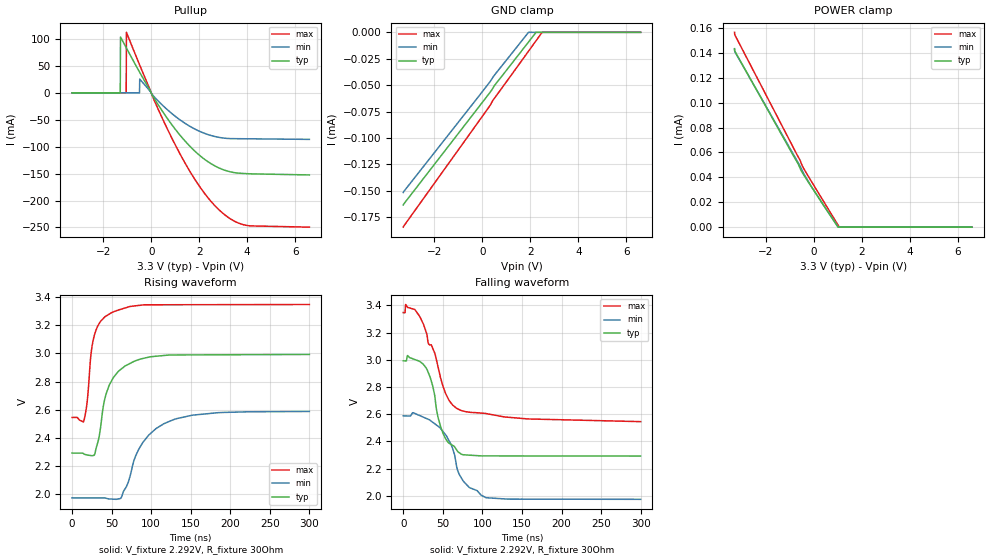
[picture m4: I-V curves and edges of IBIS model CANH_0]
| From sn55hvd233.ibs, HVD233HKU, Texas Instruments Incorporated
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|   Driver (CANH) Output/Receiver Input Model, RS=0
[Model]   CANH_0
Model_type   Open_source
Polarity   Non-Inverting
Vmeas = 1.65
Vref = 2.3
Cref = 15pF
Rref = 50
|   typ   min   max
|   (nom PVT)   (fast PVT)   (slow PVT)
C_comp   37.68p   36.61p   39.23p
|C_comp (Dom state)   44.61p   43.36p   46.74p
|C_comp (Rec state)   37.68p   36.61p   39.23p
[Voltage Range]   3.3   3   3.6
[Temperature Range]   27   150   -40
[Pullup Reference]   3.3   3   3.6
[Pulldown Reference]   -0   -0   -0
[Power Clamp Reference]   3.3   3   3.6
[GND Clamp Reference]   -0   -0   -0
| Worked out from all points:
|   slope of the pullup table from 0 to 0.495 V, typ, clamps not added: 13.8 ohm
|   falling waveform, V_fixture 2.292V, R_fixture 30Ohm: 20-80 % time 17.5ns typ, 26.4ns min, 27.6ns max; typ from 2.99 V to 2.29 V
|   rising waveform, V_fixture 2.292V, R_fixture 30Ohm: 20-80 % time 20.8ns typ, 34.2ns min, 11.9ns max; typ from 2.29 V to 2.99 V
[GND Clamp]
|   Voltage   I(typ)   I(min)   I(max)
-3.3V     -163.5uA   -151.7uA   -184.4uA
254.1mV   -58.68uA   -48.55uA   -71.25uA
462mV     -51.74uA   -41.67uA   -63.54uA
1.917V    -9.218uA   -28.75nA   -17.91uA
2.224V    -259nA     0A         -8.224uA
2.482V    0A         0A         -97.42nA
6.59V     0A         0A         0A
[Pullup]
|   Voltage   I(typ)   I(min)   I(max)
-3.3V     62.9uA     21.06uA    149.5uA
-1.29V    47.71uA    20.71uA    145uA
-1.28V    103.8mA    20.7uA     144.9uA
-1.043V   84.08mA    20.64uA    109.1uA
-1.033V   83.25mA    20.63uA    112.5mA
-488.4mV  38.82mA    17.13uA    52.54mA
-478.5mV  38.03mA    25.63mA    51.48mA
1.175V    -77.18mA   -49.34mA   -111.3mA
1.947V    -113.4mA   -69.96mA   -169.4mA
2.64V     -135.3mA   -80.89mA   -208.9mA
3.887V    -149.8mA   -85.2mA    -245.4mA
6.59V     -152.4mA   -86.35mA   -249.4mA
[POWER Clamp]
|   Voltage   I(typ)   I(min)   I(max)
-3.3V     143.4uA    142.9uA    156.5uA
-3.29V    141.5uA    141.1uA    154.6uA
-656.7mV  51.1uA     52.07uA    56.87uA
-557.7mV  46.79uA    48.59uA    53.25uA
-488.4mV  44.24uA    45.88uA    49.79uA
-132mV    33.52uA    33.68uA    37.88uA
313.5mV   20.5uA     20.37uA    23.79uA
1.006V    216.9nA    408.9nA    1.867uA
1.056V    0A         0A         301.7nA
6.59V     0A         0A         0A
[Ramp]
R_load = 30
|   typ   min   max
dV/dt_r   0.420005/2.03971e-08   0.367998/3.41559e-08   0.480883/1.18883e-08
dV/dt_f   0.420005/1.72789e-08   0.367998/2.57769e-08   0.480883/2.75924e-08
[Falling Waveform]
V_fixture = 2.292V
V_fixture_min = 1.974V
V_fixture_max = 2.545V
R_fixture = 30Ohm
C_fixture = 0F
|   Time   V(typ)   V(min)   V(max)
0s        2.992V     2.587V     3.346V
2.945ns   2.991V     2.587V     3.406V
14.46ns   3.002V     2.606V     3.37V
28.74ns   2.941V     2.569V     3.207V
37.12ns   2.81V      2.541V     3.086V
50.34ns   2.458V     2.471V     2.802V
62.04ns   2.372V     2.354V     2.669V
73.44ns   2.306V     2.131V     2.626V
105.1ns   2.293V     1.986V     2.604V
300ns     2.292V     1.974V     2.545V
[Rising Waveform]
V_fixture = 2.292V
V_fixture_min = 1.974V
V_fixture_max = 2.545V
R_fixture = 30Ohm
C_fixture = 0F
|   Time   V(typ)   V(min)   V(max)
0s        2.292V     1.974V     2.545V
15.72ns   2.284V     1.974V     2.536V
24.04ns   2.274V     1.974V     2.997V
28.12ns   2.277V     1.974V     3.126V
41.47ns   2.678V     1.974V     3.259V
50.03ns   2.805V     1.966V     3.289V
62.04ns   2.888V     1.975V     3.313V
84.52ns   2.956V     2.321V     3.34V
116.1ns   2.985V     2.501V     3.345V
300ns     2.992V     2.587V     3.346V
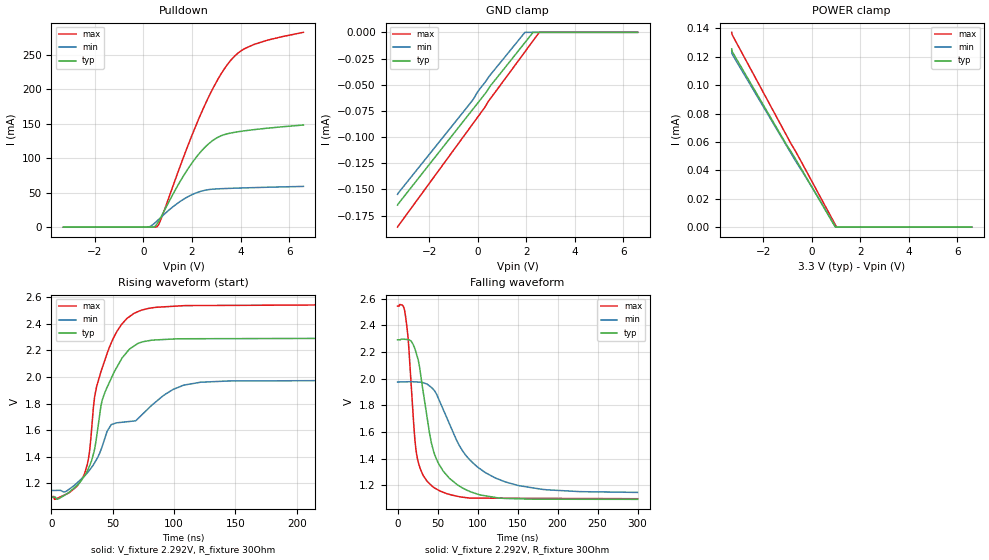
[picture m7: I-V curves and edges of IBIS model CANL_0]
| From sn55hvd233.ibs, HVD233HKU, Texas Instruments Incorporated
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|   Driver (CANL) Output/Receiver Input Model, RS=0
[Model]   CANL_0
Model_type   Open_drain
Polarity   Non-Inverting
Vmeas = 1.65
Vref = 2.3
Cref = 15pF
Rref = 50
|   typ   min   max
|   (nom PVT)   (fast PVT)   (slow PVT)
C_comp   28.10p   26.65p   30.32p
|C_comp (Dom state)   40.48p   34.89p   44.07p
|C_comp (Rec state)   28.10p   26.65p   30.32p
[Voltage Range]   3.3   3   3.6
[Temperature Range]   27   150   -40
[Pullup Reference]   3.3   3   3.6
[Pulldown Reference]   -0   -0   -0
[Power Clamp Reference]   3.3   3   3.6
[GND Clamp Reference]   -0   -0   -0
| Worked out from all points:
|   slope of the pulldown table from 0 to 0.495 V, typ, clamps not added: 269 ohm
|   falling waveform, V_fixture 2.292V, R_fixture 30Ohm: 20-80 % time 25.9ns typ, 51.6ns min, 11.5ns max; typ from 2.29 V to 1.09 V
|   rising waveform, V_fixture 2.292V, R_fixture 30Ohm: 20-80 % time 20.9ns typ, 52.6ns min, 18.5ns max; typ from 1.09 V to 2.29 V
[Pulldown]
|   Voltage   I(typ)   I(min)   I(max)
-3.3V     -104.5nA   -151.2nA   -93.38nA
145.2mV   268.4nA    71.94uA    253.2nA
422.4mV   273.8uA    4.681mA    2.136uA
561mV     4.833mA    9.079mA    726.5uA
788.7mV   19.3mA     16.59mA    17.81mA
1.531V    67.64mA    37.8mA     90.46mA
2.224V    103.8mA    50.46mA    152.9mA
2.838V    125.4mA    55.1mA     199.9mA
3.472V    135.7mA    56.23mA    236.8mA
3.947V    138.8mA    56.8mA     254.2mA
4.531V    141.5mA    57.41mA    265mA
6.59V     148.3mA    59.17mA    282.9mA
[GND Clamp]
|   Voltage   I(typ)   I(min)   I(max)
-3.3V     -164.9uA   -154.7uA   -186uA
-260.7mV  -75.27uA   -66.32uA   -89.26uA
16.5mV    -67.12uA   -56.26uA   -80.46uA
353.1mV   -57.16uA   -46.14uA   -69.44uA
561mV     -50.02uA   -39.45uA   -62.1uA
1.947V    -9.81uA    -35.41nA   -18.63uA
2.274V    -275.6nA   0A         -8.321uA
2.531V    0A         0A         -197nA
6.59V     0A         0A         0A
[POWER Clamp]
|   Voltage   I(typ)   I(min)   I(max)
-3.3V     125.5uA    124uA      137.2uA
-3.29V    123.8uA    122.1uA    135.7uA
-3.251V   122.7uA    120.9uA    134.4uA
-1.053V   58.3uA     57.62uA    64.9uA
-656.7mV  47.53uA    46.29uA    52.96uA
-102.3mV  31.36uA    31.16uA    35.55uA
966.9mV   60.4nA     558.5nA    1.724uA
1.016V    0A         0A         157nA
6.59V     0A         0A         0A
[Ramp]
R_load = 30
|   typ   min   max
dV/dt_r   0.71867/2.06378e-08   0.497274/5.2294e-08   0.867754/1.84855e-08
dV/dt_f   0.71867/2.56336e-08   0.497274/5.12522e-08   0.867754/1.14909e-08
[Falling Waveform]
V_fixture = 2.292V
V_fixture_min = 1.975V
V_fixture_max = 2.545V
R_fixture = 30Ohm
C_fixture = 0F
|   Time   V(typ)   V(min)   V(max)
0s        2.292V     1.975V     2.545V
7.232ns   2.297V     1.976V     2.544V
10.69ns   2.295V     1.977V     2.436V
21.45ns   2.227V     1.976V     1.558V
24.59ns   2.166V     1.975V     1.407V
43.13ns   1.498V     1.93V      1.193V
56.78ns   1.308V     1.773V     1.148V
81.43ns   1.179V     1.457V     1.11V
122ns     1.109V     1.255V     1.103V
300ns     1.094V     1.146V     1.099V
[Rising Waveform]
V_fixture = 2.292V
V_fixture_min = 1.975V
V_fixture_max = 2.545V
R_fixture = 30Ohm
C_fixture = 0F
|   Time   V(typ)   V(min)   V(max)
0s        1.094V     1.146V     1.099V
25.77ns   1.24V      1.245V     1.247V
30.88ns   1.327V     1.297V     1.425V
34.86ns   1.441V     1.349V     1.821V
40.47ns   1.788V     1.454V     2.042V
48.71ns   1.988V     1.64V      2.255V
67.32ns   2.232V     1.669V     2.479V
99.16ns   2.285V     1.906V     2.532V
121.7ns   2.288V     1.961V     2.537V
300ns     2.292V     1.975V     2.545V
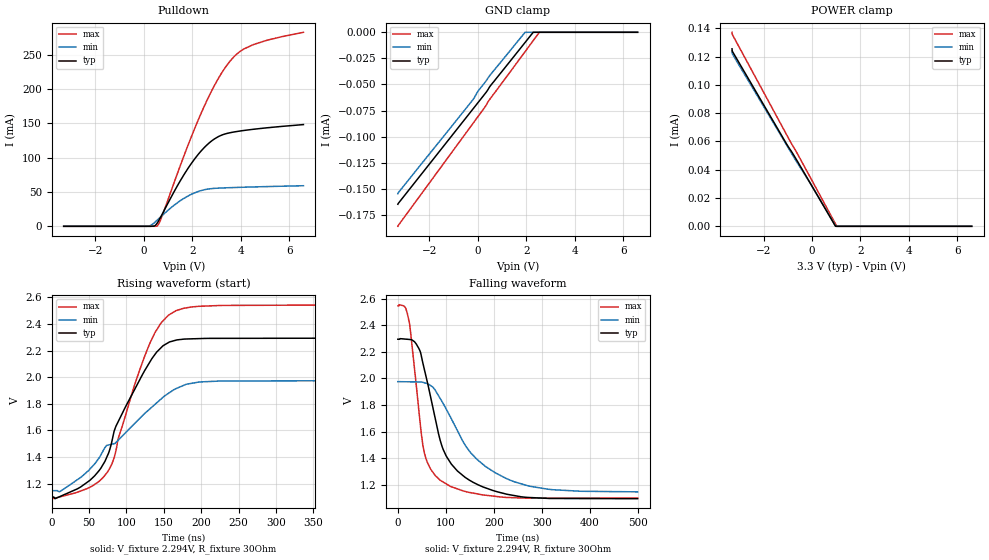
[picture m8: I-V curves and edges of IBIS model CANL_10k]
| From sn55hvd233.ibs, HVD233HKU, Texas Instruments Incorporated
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|   Driver (CANL) Output/Receiver Input Model, RS=10k
[Model]   CANL_10k
Model_type   Open_drain
Polarity   Non-Inverting
Vmeas = 1.65
Vref = 2.3
Cref = 15pF
Rref = 50
|   typ   min   max
|   (nom PVT)   (fast PVT)   (slow PVT)
C_comp   28.10p   26.65p   30.32p
|C_comp (Dom state)   40.48p   34.89p   44.07p
|C_comp (Rec state)   28.10p   26.65p   30.32p
[Voltage Range]   3.3   3   3.6
[Temperature Range]   27   150   -40
[Pullup Reference]   3.3   3   3.6
[Pulldown Reference]   -0   -0   -0
[Power Clamp Reference]   3.3   3   3.6
[GND Clamp Reference]   -0   -0   -0
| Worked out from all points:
|   slope of the pulldown table from 0 to 0.495 V, typ, clamps not added: 269 ohm
|   falling waveform, V_fixture 2.294V, R_fixture 30Ohm: 20-80 % time 60.4ns typ, 98.9ns min, 30.2ns max; typ from 2.29 V to 1.09 V
|   rising waveform, V_fixture 2.294V, R_fixture 30Ohm: 20-80 % time 57.1ns typ, 89.3ns min, 48.3ns max; typ from 1.09 V to 2.29 V
[Pulldown]
|   Voltage   I(typ)   I(min)   I(max)
-3.3V     -104.5nA   -151.2nA   -93.38nA
145.2mV   268.4nA    71.94uA    253.2nA
422.4mV   273.8uA    4.681mA    2.136uA
561mV     4.833mA    9.079mA    726.5uA
788.7mV   19.3mA     16.59mA    17.81mA
1.531V    67.64mA    37.8mA     90.46mA
2.224V    103.8mA    50.46mA    152.9mA
2.838V    125.4mA    55.1mA     199.9mA
3.472V    135.7mA    56.23mA    236.8mA
3.947V    138.8mA    56.8mA     254.2mA
4.531V    141.5mA    57.41mA    265mA
6.59V     148.3mA    59.17mA    282.9mA
[GND Clamp]
|   Voltage   I(typ)   I(min)   I(max)
-3.3V     -164.9uA   -154.7uA   -186uA
-260.7mV  -75.27uA   -66.32uA   -89.26uA
16.5mV    -67.12uA   -56.26uA   -80.46uA
353.1mV   -57.16uA   -46.14uA   -69.44uA
561mV     -50.02uA   -39.45uA   -62.1uA
1.947V    -9.81uA    -35.41nA   -18.63uA
2.274V    -275.6nA   0A         -8.321uA
2.531V    0A         0A         -197nA
6.59V     0A         0A         0A
[POWER Clamp]
|   Voltage   I(typ)   I(min)   I(max)
-3.3V     125.5uA    124uA      137.2uA
-3.29V    123.8uA    122.1uA    135.7uA
-3.251V   122.7uA    120.9uA    134.4uA
-1.053V   58.3uA     57.62uA    64.9uA
-656.7mV  47.53uA    46.29uA    52.96uA
-102.3mV  31.36uA    31.16uA    35.55uA
966.9mV   60.4nA     558.5nA    1.724uA
1.016V    0A         0A         157nA
6.59V     0A         0A         0A
[Ramp]
R_load = 30
|   typ   min   max
dV/dt_r   0.719469/5.6909e-08   0.497274/8.85304e-08   0.867754/4.8261e-08
dV/dt_f   0.719469/5.98566e-08   0.497274/9.83517e-08   0.867754/3.01305e-08
[Falling Waveform]
V_fixture = 2.294V
V_fixture_min = 1.975V
V_fixture_max = 2.545V
R_fixture = 30Ohm
C_fixture = 0F
|   Time   V(typ)   V(min)   V(max)
0s        2.294V     1.975V     2.545V
15.59ns   2.295V     1.974V     2.533V
24.56ns   2.292V     1.974V     2.408V
46.01ns   2.207V     1.973V     1.681V
58.13ns   2.023V     1.964V     1.402V
88.25ns   1.535V     1.849V     1.234V
111.3ns   1.356V     1.698V     1.185V
151.1ns   1.23V      1.444V     1.141V
225.6ns   1.13V      1.248V     1.104V
500ns     1.095V     1.146V     1.099V
[Rising Waveform]
V_fixture = 2.294V
V_fixture_min = 1.975V
V_fixture_max = 2.545V
R_fixture = 30Ohm
C_fixture = 0F
|   Time   V(typ)   V(min)   V(max)
0s        1.095V     1.146V     1.099V
50.85ns   1.224V     1.308V     1.173V
73.91ns   1.402V     1.488V     1.282V
85.83ns   1.63V      1.509V     1.446V
110.2ns   1.9V       1.648V     1.932V
130.9ns   2.111V     1.76V      2.25V
146.4ns   2.222V     1.837V     2.409V
166.4ns   2.278V     1.914V     2.5V
225.6ns   2.292V     1.971V     2.539V
500ns     2.294V     1.975V     2.545V
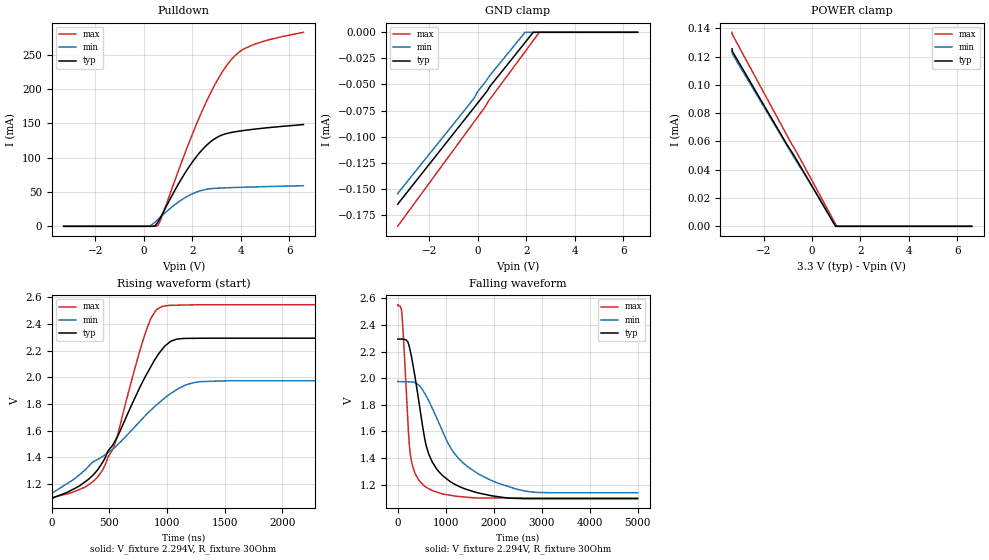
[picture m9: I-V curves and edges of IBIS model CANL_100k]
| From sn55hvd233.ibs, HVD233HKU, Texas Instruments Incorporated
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|   Driver (CANL) Output/Receiver Input Model, RS=100k
[Model]   CANL_100k
Model_type   Open_drain
Polarity   Non-Inverting
Vmeas = 1.65
Vref = 2.3
Cref = 15pF
Rref = 50
|   typ   min   max
|   (nom PVT)   (fast PVT)   (slow PVT)
C_comp   28.10p   26.65p   30.32p
|C_comp (Dom state)   40.48p   34.89p   44.07p
|C_comp (Rec state)   28.10p   26.65p   30.32p
[Voltage Range]   3.3   3   3.6
[Temperature Range]   27   150   -40
[Pullup Reference]   3.3   3   3.6
[Pulldown Reference]   -0   -0   -0
[Power Clamp Reference]   3.3   3   3.6
[GND Clamp Reference]   -0   -0   -0
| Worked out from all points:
|   slope of the pulldown table from 0 to 0.495 V, typ, clamps not added: 269 ohm
|   falling waveform, V_fixture 2.294V, R_fixture 30Ohm: 20-80 % time 443ns typ, 899ns min, 153ns max; typ from 2.29 V to 1.09 V
|   rising waveform, V_fixture 2.294V, R_fixture 30Ohm: 20-80 % time 423ns typ, 638ns min, 301ns max; typ from 1.09 V to 2.29 V
[Pulldown]
|   Voltage   I(typ)   I(min)   I(max)
-3.3V     -104.5nA   -151.2nA   -93.38nA
145.2mV   268.4nA    71.94uA    253.2nA
422.4mV   273.8uA    4.681mA    2.136uA
561mV     4.833mA    9.079mA    726.5uA
788.7mV   19.3mA     16.59mA    17.81mA
1.531V    67.64mA    37.8mA     90.46mA
2.224V    103.8mA    50.46mA    152.9mA
2.838V    125.4mA    55.1mA     199.9mA
3.472V    135.7mA    56.23mA    236.8mA
3.947V    138.8mA    56.8mA     254.2mA
4.531V    141.5mA    57.41mA    265mA
6.59V     148.3mA    59.17mA    282.9mA
[GND Clamp]
|   Voltage   I(typ)   I(min)   I(max)
-3.3V     -164.9uA   -154.7uA   -186uA
-260.7mV  -75.27uA   -66.32uA   -89.26uA
16.5mV    -67.12uA   -56.26uA   -80.46uA
353.1mV   -57.16uA   -46.14uA   -69.44uA
561mV     -50.02uA   -39.45uA   -62.1uA
1.947V    -9.81uA    -35.41nA   -18.63uA
2.274V    -275.6nA   0A         -8.321uA
2.531V    0A         0A         -197nA
6.59V     0A         0A         0A
[POWER Clamp]
|   Voltage   I(typ)   I(min)   I(max)
-3.3V     125.5uA    124uA      137.2uA
-3.29V    123.8uA    122.1uA    135.7uA
-3.251V   122.7uA    120.9uA    134.4uA
-1.053V   58.3uA     57.62uA    64.9uA
-656.7mV  47.53uA    46.29uA    52.96uA
-102.3mV  31.36uA    31.16uA    35.55uA
966.9mV   60.4nA     558.5nA    1.724uA
1.016V    0A         0A         157nA
6.59V     0A         0A         0A
[Ramp]
R_load = 30
|   typ   min   max
dV/dt_r   0.719469/4.20234e-07   0.501556/6.37018e-07   0.867754/3.01847e-07
dV/dt_f   0.719469/4.39533e-07   0.501569/8.9218e-07   0.867754/1.53264e-07
[Falling Waveform]
V_fixture = 2.294V
V_fixture_min = 1.975V
V_fixture_max = 2.545V
R_fixture = 30Ohm
C_fixture = 0F
|   Time   V(typ)   V(min)   V(max)
0s        2.294V     1.975V     2.545V
83.64ns   2.294V     1.974V     2.488V
222.2ns   2.257V     1.972V     1.591V
262.4ns   2.2V       1.972V     1.422V
548.2ns   1.569V     1.894V     1.192V
718.9ns   1.37V      1.773V     1.156V
929.7ns   1.269V     1.604V     1.131V
1.289us   1.185V     1.388V     1.111V
1.916us   1.12V      1.237V     1.101V
5us       1.095V     1.139V     1.099V
[Rising Waveform]
V_fixture = 2.294V
V_fixture_min = 1.975V
V_fixture_max = 2.545V
R_fixture = 30Ohm
C_fixture = 0F
|   Time   V(typ)   V(min)   V(max)
0s        1.095V     1.139V     1.099V
285ns     1.214V     1.302V     1.176V
440.8ns   1.362V     1.406V     1.305V
554.9ns   1.531V     1.481V     1.52V
827ns     2.029V     1.727V     2.37V
909.1ns   2.152V     1.793V     2.508V
956ns     2.208V     1.828V     2.531V
1.082us   2.286V     1.907V     2.541V
1.289us   2.293V     1.968V     2.544V
5us       2.294V     1.975V     2.545V
